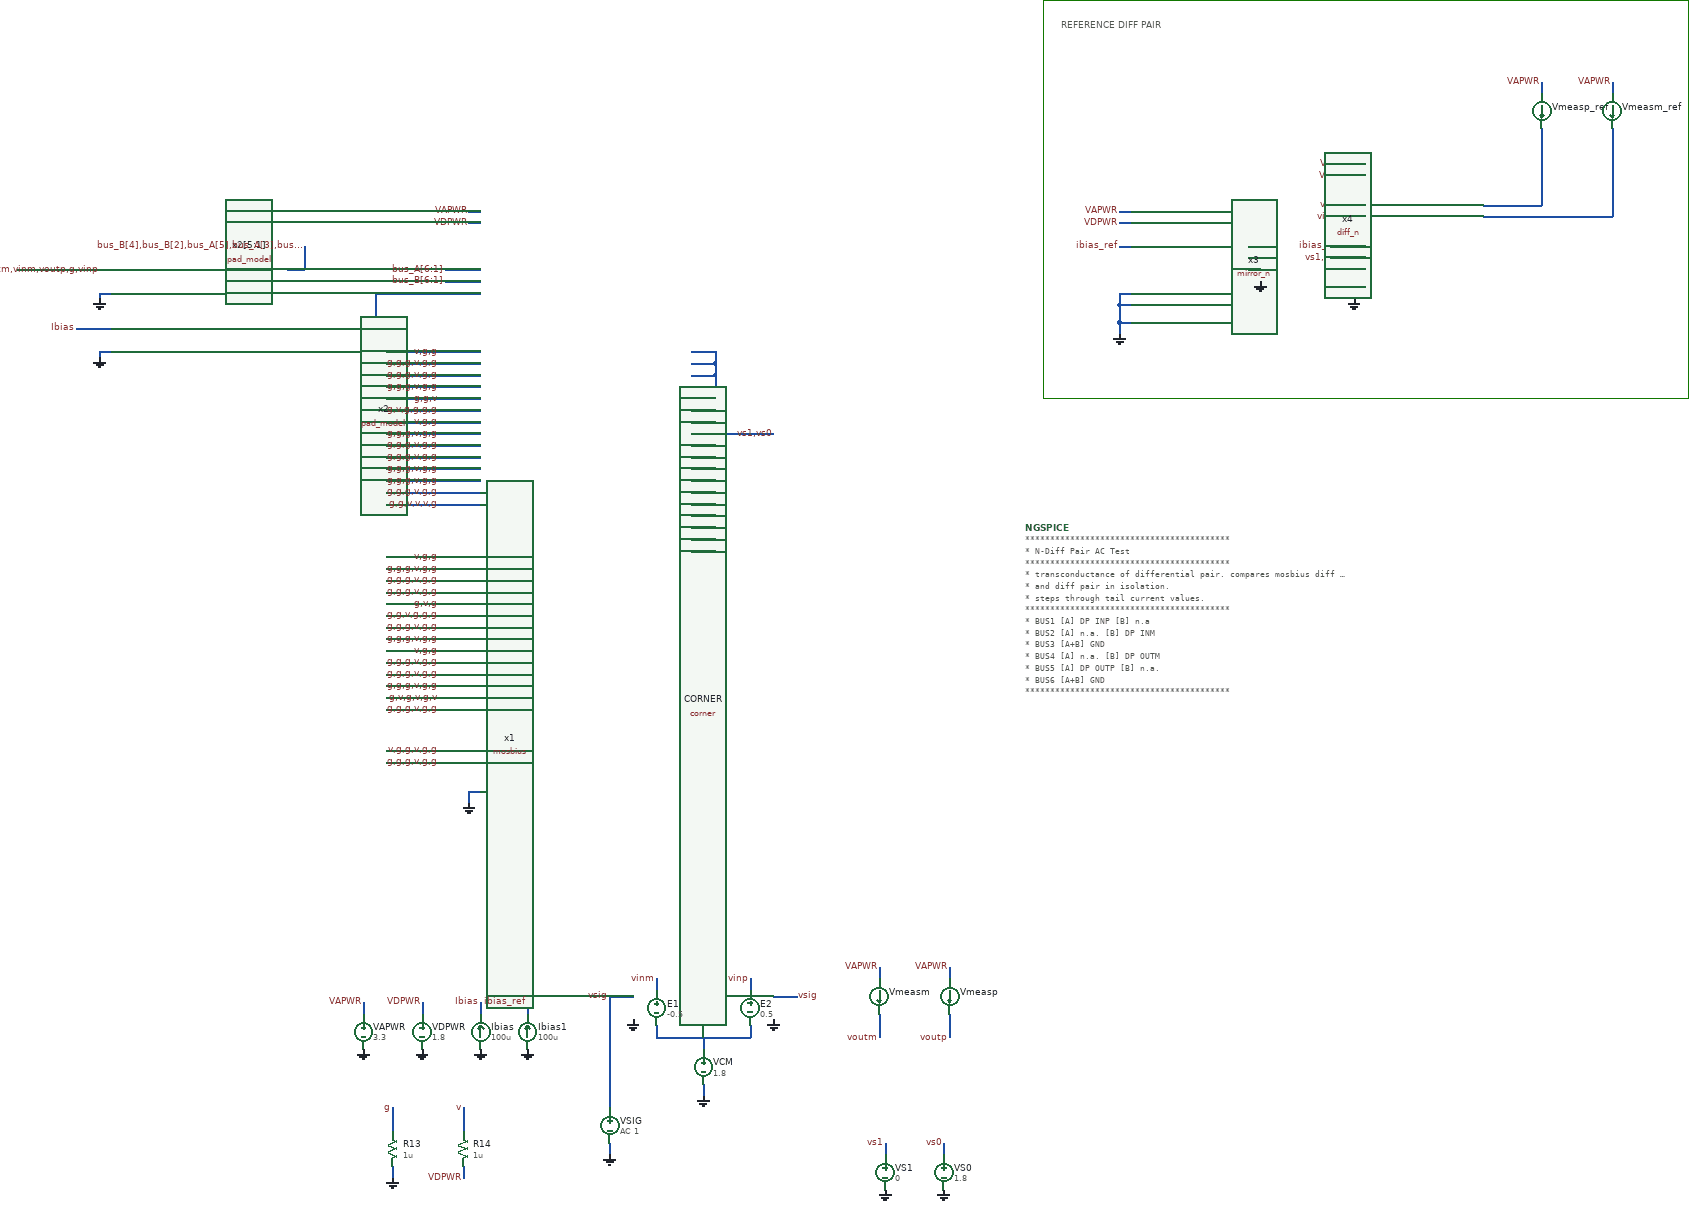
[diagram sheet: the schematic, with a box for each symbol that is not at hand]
v {xschem version=3.4.8RC file_version=1.2}
G {}
K {}
V {}
S {}
E {}
L 4 1260 -1610 1260 -930 {}
L 4 1260 -1610 2360 -1610 {}
L 4 1260 -930 2360 -930 {}
L 4 2360 -1610 2360 -930 {}
T {REFERENCE DIFF PAIR} 1290 -1580 0 0 0.4 0.4 {}
N 100 100 100 120 {
lab=VAPWR}
N 200 100 200 120 {
lab=VDPWR}
N 280 -1230 300 -1230 {
lab=VDPWR}
N 280 -1250 300 -1250 {
lab=VAPWR}
N 280 -260 280 -240 {
lab=GND}
N 280 -260 300 -260 {
lab=GND}
N 300 100 300 120 {
lab=Ibias}
N 660 -970 700 -970 {
lab=GND}
N 660 -950 700 -950 {
lab=GND}
N 660 -930 700 -930 {
lab=GND}
N 660 -910 700 -910 {
lab=GND}
N 660 -890 700 -890 {
lab=GND}
N 660 -850 700 -850 {
lab=GND}
N 660 -810 700 -810 {
lab=GND}
N 660 -790 700 -790 {
lab=GND}
N 660 -770 700 -770 {
lab=GND}
N 660 -750 700 -750 {
lab=GND}
N 660 -730 700 -730 {
lab=GND}
N 660 -710 700 -710 {
lab=GND}
N 660 -690 700 -690 {
lab=GND}
N 660 -670 700 -670 {
lab=GND}
N 700 -970 700 -640 {
lab=GND}
N 680 240 680 260 {
lab=GND}
N 760 60 760 80 {
lab=vinp}
N 660 -990 700 -990 {
lab=GND}
N 700 -990 700 -970 {
lab=GND}
N 150 380 150 400 {
lab=GND}
N 150 280 150 320 {
lab=g}
N 270 280 270 320 {
lab=v}
N 270 380 270 400 {
lab=VDPWR}
N 1790 -1310 1810 -1310 {
lab=VDPWR}
N 1790 -1330 1810 -1330 {
lab=VAPWR}
N 1790 -1120 1790 -1100 {
lab=GND}
N 1790 -1120 1810 -1120 {
lab=GND}
N 1390 -1230 1410 -1230 {
lab=VDPWR}
N 1390 -1250 1410 -1250 {
lab=VAPWR}
N 1390 -1060 1390 -1040 {
lab=GND}
N 1390 -1060 1410 -1060 {
lab=GND}
N 1390 -1090 1410 -1090 {
lab=GND}
N 1390 -1090 1390 -1060 {
lab=GND}
N 1390 -1110 1410 -1110 {
lab=GND}
N 1390 -1110 1390 -1090 {
lab=GND}
N 1630 -1170 1630 -1130 {
lab=GND}
N 1610 -1170 1630 -1170 {
lab=GND}
N 1610 -1150 1630 -1150 {
lab=GND}
N 380 100 380 120 {
lab=ibias_ref}
N 1390 -1190 1410 -1190 {
lab=ibias_ref}
N 1790 -1150 1810 -1150 {
lab=GND}
N 1790 -1150 1790 -1120 {
lab=GND}
N 1750 -1170 1810 -1170 {
lab=vs1,vs0}
N 1770 -1260 1810 -1260 {
lab=vinp}
N 1770 -1240 1810 -1240 {
lab=vinm}
N 1750 -1190 1810 -1190 {
lab=ibias_ref}
N -490 -1150 -330 -1150 {
lab=voutm,vinm,voutp,g,vinp}
N -390 -1050 -330 -1050 {
lab=Ibias}
N 100 -1050 120 -1050 {
lab=#net1}
N 120 -1110 120 -1050 {
lab=#net1}
N 120 -1110 300 -1110 {
lab=#net1}
N -350 -1010 -350 -1000 {
lab=GND}
N -350 -1010 -330 -1010 {
lab=GND}
N -350 -1110 -350 -1100 {
lab=GND}
N -350 -1110 -330 -1110 {
lab=GND}
N 600 60 600 80 {
lab=vinm}
N 600 140 600 160 {
lab=#net2}
N 600 160 760 160 {
lab=#net2}
N 760 140 760 160 {
lab=#net2}
N 680 160 680 180 {
lab=#net2}
N 1100 40 1100 60 {
lab=VAPWR}
N 980 40 980 60 {
lab=VAPWR}
N 980 120 980 160 {
lab=voutm}
N 1100 120 1100 160 {
lab=voutp}
N 2230 -1470 2230 -1450 {
lab=VAPWR}
N 2110 -1470 2110 -1450 {
lab=VAPWR}
N 2010 -1260 2110 -1260 {
lab=#net3}
N 2110 -1390 2110 -1260 {
lab=#net3}
N 2010 -1240 2230 -1240 {
lab=#net4}
N 2230 -1390 2230 -1240 {
lab=#net4}
N 660 -1010 700 -1010 {
lab=GND}
N 700 -1010 700 -990 {
lab=GND}
N 660 -870 800 -870 {
lab=vs1,vs0}
N 660 -830 700 -830 {
lab=GND}
N 520 340 520 360 {
lab=GND}
N 520 90 520 280 {
lab=vsig}
N 520 90 560 90 {
lab=vsig}
N 800 90 840 90 {
lab=vsig}
N 990 340 990 360 {
lab=vs1}
N 1090 340 1090 360 {
lab=vs0}
N 1610 -1190 1630 -1190 {
lab=GND}
N 1630 -1190 1630 -1170 {
lab=GND}
N 240 -1150 300 -1150 {lab=bus_A[6:1]}
N 240 -1130 300 -1130 {lab=bus_B[6:1]}
N -30 -1050 100 -1050 {lab=#net1}
N -30 -1150 -0 -1150 {lab=bus_B[4],bus_B[2],bus_A[5],bus_A[3],bus_A[1]}
N 0 -1190 0 -1150 {lab=bus_B[4],bus_B[2],bus_A[5],bus_A[3],bus_A[1]}
N 140 -420 300 -420 {
lab=g,v,g,v,g,v}
N 140 -440 300 -440 {
lab=g,g,g,v,g,g}
N 140 -460 300 -460 {
lab=g,g,g,v,g,g}
N 140 -480 300 -480 {
lab=g,g,g,v,g,g}
N 140 -500 300 -500 {
lab=v,g,g}
N 140 -520 300 -520 {
lab=g,g,g,v,g,g}
N 140 -540 300 -540 {
lab=g,g,g,v,g,g}
N 140 -560 300 -560 {
lab=g,g,v,g,g,g}
N 140 -580 300 -580 {
lab=g,v,g}
N 140 -600 300 -600 {
lab=g,g,g,v,g,g}
N 140 -620 300 -620 {
lab=g,g,g,v,g,g}
N 140 -640 300 -640 {
lab=g,g,g,v,g,g}
N 140 -660 300 -660 {
lab=v,g,g}
N 140 -750 300 -750 {
lab=g,g,v,v,v,g}
N 140 -770 300 -770 {
lab=g,g,g,v,g,g}
N 140 -790 300 -790 {
lab=g,g,g,v,g,g}
N 140 -810 300 -810 {
lab=g,g,g,v,g,g}
N 140 -830 300 -830 {
lab=g,g,g,v,g,g}
N 140 -850 300 -850 {
lab=g,g,g,v,g,g}
N 140 -870 300 -870 {
lab=g,g,g,v,g,g}
N 140 -910 300 -910 {
lab=g,v,g,g,g,g}
N 140 -950 300 -950 {
lab=g,g,g,v,g,g}
N 140 -970 300 -970 {
lab=g,g,g,v,g,g}
N 140 -890 300 -890 {
lab=v,g,g}
N 140 -930 300 -930 {
lab=g,g,v}
N 140 -330 300 -330 {
lab=v,g,g,v,g,g}
N 140 -1010 300 -1010 {
lab=v,g,g}
N 140 -990 300 -990 {
lab=g,g,g,v,g,g}
N 140 -310 300 -310 {lab=g,g,g,v,g,g}
N 140 -400 300 -400 {lab=g,g,g,v,g,g}
C {mosbius.sym} 300 -240 0 0 {name=x1}
C {devices/vsource.sym} 100 150 0 0 {name=VAPWR value=3.3}
C {devices/gnd.sym} 100 180 0 0 {name=l1 lab=GND}
C {devices/lab_pin.sym} 100 100 1 0 {name=p2 sig_type=std_logic lab=VAPWR}
C {devices/vsource.sym} 200 150 0 0 {name=VDPWR value=1.8}
C {devices/gnd.sym} 200 180 0 0 {name=l2 lab=GND}
C {devices/lab_pin.sym} 200 100 1 0 {name=p3 sig_type=std_logic lab=VDPWR}
C {devices/lab_pin.sym} 280 -1250 0 0 {name=p4 sig_type=std_logic lab=VAPWR}
C {devices/lab_pin.sym} 280 -1230 0 0 {name=p5 sig_type=std_logic lab=VDPWR}
C {devices/gnd.sym} 280 -240 0 0 {name=l3 lab=GND}
C {devices/isource.sym} 300 150 2 1 {name=Ibias value=100u}
C {devices/gnd.sym} 300 180 0 0 {name=l4 lab=GND}
C {devices/lab_pin.sym} 300 100 1 0 {name=p1 sig_type=std_logic lab=Ibias}
C {devices/gnd.sym} 700 -640 0 0 {name=l5 lab=GND}
C {devices/vsource.sym} 520 310 0 0 {name=VSIG value="AC 1"}
C {devices/vsource.sym} 680 210 0 0 {name=VCM value=1.8}
C {devices/gnd.sym} 680 260 0 0 {name=l9 lab=GND}
C {devices/lab_pin.sym} 760 60 1 0 {name=p10 sig_type=std_logic lab=vinp}
C {sky130_fd_pr/corner.sym} 970 -300 0 0 {name=CORNER only_toplevel=true corner=tt}
C {devices/code_shown.sym} 1230 -710 0 0 {name=NGSPICE only_toplevel=true value=
"
*****************************************
* N-Diff Pair AC Test
*****************************************
* transconductance of differential pair. compares mosbius diff pair
* and diff pair in isolation. 
* steps through tail current values.
*****************************************
* BUS1 [A] DP INP   [B] n.a
* BUS2 [A] n.a.     [B] DP INM
* BUS3 [A+B] GND
* BUS4 [A] n.a.     [B] DP OUTM
* BUS5 [A] DP OUTP  [B] n.a.
* BUS6 [A+B] GND
*****************************************
.control
   save all
   set temp = 27
   foreach vcm_val 0.75 1 1.25 1.5 1.75 2
      alter vcm $vcm_val
      ac dec 51 1Meg 10G
   end
   let mosb_0p75 = ac1.i(vmeasp)-ac1.i(vmeasm)
   let base_0p75 = ac1.i(vmeasp_ref)-ac1.i(vmeasm_ref)
   let mosb_1p00 = ac2.i(vmeasp)-ac2.i(vmeasm)
   let base_1p00 = ac2.i(vmeasp_ref)-ac2.i(vmeasm_ref)
   let mosb_1p25 = ac3.i(vmeasp)-ac3.i(vmeasm)
   let base_1p25 = ac3.i(vmeasp_ref)-ac3.i(vmeasm_ref)
   let mosb_1p50 = ac4.i(vmeasp)-ac4.i(vmeasm)
   let base_1p50 = ac4.i(vmeasp_ref)-ac4.i(vmeasm_ref)
   let mosb_1p75 = ac5.i(vmeasp)-ac5.i(vmeasm)
   let base_1p75 = ac5.i(vmeasp_ref)-ac5.i(vmeasm_ref)
   plot mosb_0p75 base_0p75 mosb_1p00 base_1p00 mosb_1p25 base_1p25 mosb_1p50 base_1p50 mosb_1p75 base_1p75
.endc
"}
C {devices/gnd.sym} 150 400 0 0 {name=l10 lab=GND}
C {devices/res.sym} 150 350 0 0 {name=R13
value=1u
footprint=1206
device=resistor
m=1}
C {devices/lab_pin.sym} 150 280 0 0 {name=p17 sig_type=std_logic lab=g}
C {devices/res.sym} 270 350 0 0 {name=R14
value=1u
footprint=1206
device=resistor
m=1}
C {devices/lab_pin.sym} 270 400 3 0 {name=p18 sig_type=std_logic lab=VDPWR}
C {devices/lab_pin.sym} 270 280 0 0 {name=p19 sig_type=std_logic lab=v}
C {devices/lab_pin.sym} 1790 -1330 0 0 {name=p13 sig_type=std_logic lab=VAPWR}
C {devices/lab_pin.sym} 1790 -1310 0 0 {name=p23 sig_type=std_logic lab=VDPWR}
C {devices/gnd.sym} 1790 -1100 0 0 {name=l7 lab=GND}
C {mirror_n.sym} 1460 -1190 0 0 {name=x3}
C {devices/lab_pin.sym} 1390 -1250 0 0 {name=p26 sig_type=std_logic lab=VAPWR}
C {devices/lab_pin.sym} 1390 -1230 0 0 {name=p29 sig_type=std_logic lab=VDPWR}
C {devices/gnd.sym} 1390 -1040 0 0 {name=l8 lab=GND}
C {devices/gnd.sym} 1630 -1130 0 0 {name=l11 lab=GND}
C {devices/isource.sym} 380 150 2 1 {name=Ibias1 value=100u}
C {devices/gnd.sym} 380 180 0 0 {name=l12 lab=GND}
C {devices/lab_pin.sym} 380 100 1 0 {name=p30 sig_type=std_logic lab=ibias_ref}
C {devices/lab_pin.sym} 1390 -1190 0 0 {name=p31 sig_type=std_logic lab=ibias_ref}
C {devices/lab_pin.sym} 1770 -1260 2 1 {name=p12 sig_type=std_logic lab=vinp}
C {devices/lab_pin.sym} 1770 -1240 2 1 {name=p32 sig_type=std_logic lab=vinm}
C {devices/lab_wire.sym} 1770 -1170 0 0 {name=p35 sig_type=std_logic lab=vs1,vs0}
C {devices/lab_wire.sym} 1770 -1190 0 0 {name=p36 sig_type=std_logic lab=ibias_ref}
C {pad_model.sym} -180 -1130 0 0 {name=x2[5:1]}
C {devices/lab_wire.sym} -350 -1150 0 0 {name=p9 sig_type=std_logic lab=voutm,vinm,voutp,g,vinp}
C {pad_model.sym} -180 -1030 0 0 {name=x2}
C {devices/lab_pin.sym} -390 -1050 0 0 {name=p6 sig_type=std_logic lab=Ibias}
C {devices/gnd.sym} -350 -1100 0 0 {name=l14 lab=GND}
C {devices/gnd.sym} -350 -1000 0 0 {name=l15 lab=GND}
C {devices/lab_pin.sym} 600 60 1 0 {name=p8 sig_type=std_logic lab=vinm}
C {devices/ammeter.sym} 980 90 0 0 {name=Vmeasm}
C {devices/ammeter.sym} 1100 90 0 0 {name=Vmeasp}
C {devices/lab_pin.sym} 980 40 1 0 {name=p28 sig_type=std_logic lab=VAPWR}
C {devices/lab_pin.sym} 1100 40 1 0 {name=p37 sig_type=std_logic lab=VAPWR}
C {devices/lab_pin.sym} 980 160 3 0 {name=p38 sig_type=std_logic lab=voutm}
C {devices/lab_pin.sym} 1100 160 3 0 {name=p59 sig_type=std_logic lab=voutp}
C {diff_n.sym} 1910 -1210 0 0 {name=x4}
C {devices/ammeter.sym} 2110 -1420 0 0 {name=Vmeasp_ref}
C {devices/ammeter.sym} 2230 -1420 0 0 {name=Vmeasm_ref}
C {devices/lab_pin.sym} 2110 -1470 1 0 {name=p33 sig_type=std_logic lab=VAPWR}
C {devices/lab_pin.sym} 2230 -1470 1 0 {name=p34 sig_type=std_logic lab=VAPWR}
C {devices/lab_wire.sym} 800 -870 0 0 {name=p14 sig_type=std_logic lab=vs1,vs0}
C {devices/vcvs.sym} 600 110 0 0 {name=E1 value=-0.5}
C {devices/vcvs.sym} 760 110 0 1 {name=E2 value=0.5}
C {devices/gnd.sym} 520 360 0 0 {name=l6 lab=GND}
C {devices/gnd.sym} 560 130 0 0 {name=l13 lab=GND}
C {devices/gnd.sym} 800 130 0 0 {name=l16 lab=GND}
C {devices/lab_pin.sym} 520 90 0 0 {name=p60 sig_type=std_logic lab=vsig}
C {devices/lab_pin.sym} 840 90 0 1 {name=p61 sig_type=std_logic lab=vsig}
C {devices/vsource.sym} 990 390 0 0 {name=VS1 value=0}
C {devices/gnd.sym} 990 420 0 0 {name=l17 lab=GND}
C {devices/lab_pin.sym} 990 340 1 0 {name=p62 sig_type=std_logic lab=vs1}
C {devices/vsource.sym} 1090 390 0 0 {name=VS0 value=1.8}
C {devices/gnd.sym} 1090 420 0 0 {name=l18 lab=GND}
C {devices/lab_pin.sym} 1090 340 1 0 {name=p63 sig_type=std_logic lab=vs0}
C {devices/lab_wire.sym} 240 -1150 0 0 {name=p11 sig_type=std_logic lab=bus_A[6:1]}
C {devices/lab_wire.sym} 240 -1130 0 0 {name=p56 sig_type=std_logic lab=bus_B[6:1]}
C {devices/lab_wire.sym} 0 -1190 0 0 {name=p64 sig_type=std_logic lab=bus_B[4],bus_B[2],bus_A[5],bus_A[3],bus_A[1]}
C {devices/lab_wire.sym} 230 -500 0 0 {name=p27 sig_type=std_logic lab=v,g,g}
C {devices/lab_wire.sym} 230 -560 0 0 {name=p40 sig_type=std_logic lab=g,g,v,g,g,g}
C {devices/lab_wire.sym} 230 -580 0 0 {name=p41 sig_type=std_logic lab=g,v,g}
C {devices/lab_wire.sym} 230 -640 0 0 {name=p44 sig_type=std_logic lab=g,g,g,v,g,g}
C {devices/lab_wire.sym} 230 -660 0 0 {name=p45 sig_type=std_logic lab=v,g,g}
C {devices/lab_wire.sym} 230 -750 0 0 {name=p46 sig_type=std_logic lab=g,g,v,v,v,g}
C {devices/lab_wire.sym} 230 -910 0 0 {name=p53 sig_type=std_logic lab=g,v,g,g,g,g}
C {devices/lab_wire.sym} 230 -890 0 0 {name=p57 sig_type=std_logic lab=v,g,g}
C {devices/lab_wire.sym} 230 -930 0 0 {name=p58 sig_type=std_logic lab=g,g,v}
C {devices/lab_wire.sym} 230 -330 0 0 {name=p25 sig_type=std_logic lab=v,g,g,v,g,g}
C {devices/lab_wire.sym} 230 -1010 0 0 {name=p15 sig_type=std_logic lab=v,g,g}
C {devices/lab_wire.sym} 230 -310 0 0 {name=p65 sig_type=std_logic lab=g,g,g,v,g,g}
C {devices/lab_wire.sym} 230 -770 0 0 {name=p7 sig_type=std_logic lab=g,g,g,v,g,g}
C {devices/lab_wire.sym} 230 -790 0 0 {name=p47 sig_type=std_logic lab=g,g,g,v,g,g}
C {devices/lab_wire.sym} 230 -810 0 0 {name=p48 sig_type=std_logic lab=g,g,g,v,g,g}
C {devices/lab_wire.sym} 230 -830 0 0 {name=p49 sig_type=std_logic lab=g,g,g,v,g,g}
C {devices/lab_wire.sym} 230 -850 0 0 {name=p50 sig_type=std_logic lab=g,g,g,v,g,g}
C {devices/lab_wire.sym} 230 -870 0 0 {name=p51 sig_type=std_logic lab=g,g,g,v,g,g}
C {devices/lab_wire.sym} 230 -950 0 0 {name=p52 sig_type=std_logic lab=g,g,g,v,g,g}
C {devices/lab_wire.sym} 230 -970 0 0 {name=p54 sig_type=std_logic lab=g,g,g,v,g,g}
C {devices/lab_wire.sym} 230 -990 0 0 {name=p55 sig_type=std_logic lab=g,g,g,v,g,g}
C {devices/lab_wire.sym} 230 -620 0 0 {name=p16 sig_type=std_logic lab=g,g,g,v,g,g}
C {devices/lab_wire.sym} 230 -600 0 0 {name=p20 sig_type=std_logic lab=g,g,g,v,g,g}
C {devices/lab_wire.sym} 230 -540 0 0 {name=p21 sig_type=std_logic lab=g,g,g,v,g,g}
C {devices/lab_wire.sym} 230 -520 0 0 {name=p22 sig_type=std_logic lab=g,g,g,v,g,g}
C {devices/lab_wire.sym} 230 -480 0 0 {name=p24 sig_type=std_logic lab=g,g,g,v,g,g}
C {devices/lab_wire.sym} 230 -460 0 0 {name=p39 sig_type=std_logic lab=g,g,g,v,g,g}
C {devices/lab_wire.sym} 230 -440 0 0 {name=p42 sig_type=std_logic lab=g,g,g,v,g,g}
C {devices/lab_wire.sym} 230 -420 0 0 {name=p43 sig_type=std_logic lab=g,v,g,v,g,v}
C {devices/lab_wire.sym} 230 -400 0 0 {name=p66 sig_type=std_logic lab=g,g,g,v,g,g}
